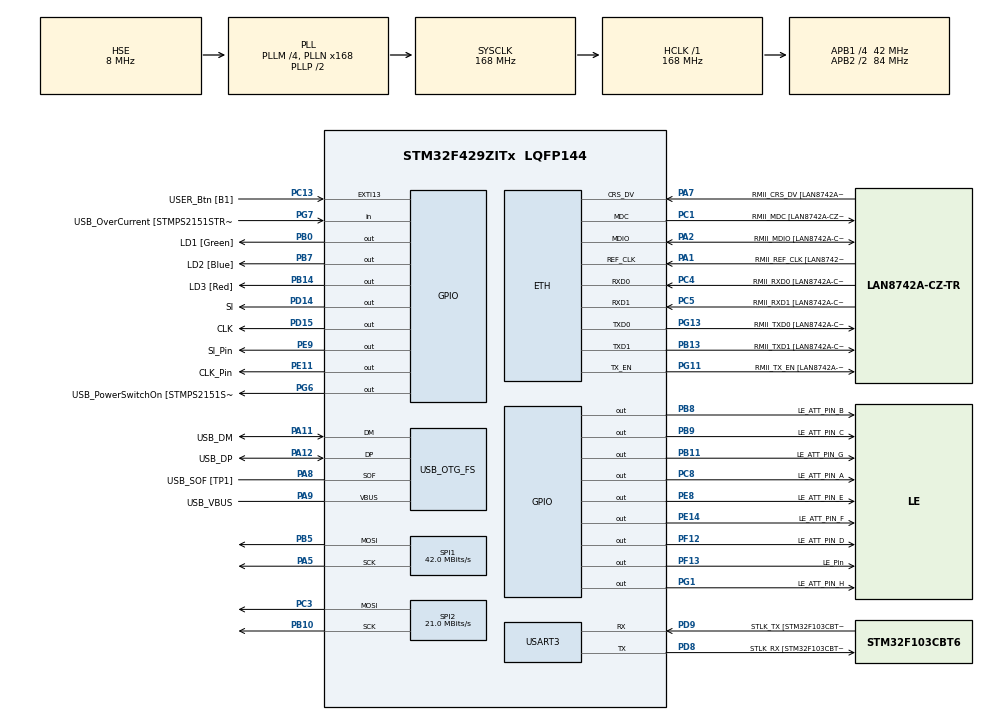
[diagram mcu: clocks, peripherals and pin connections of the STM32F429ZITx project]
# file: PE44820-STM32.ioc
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ETH.MediaInterface=HAL_ETH_RMII_MODE
ETH.PHY_Name=LAN8742A_PHY_ADDRESS
ETH.PHY_Value=0
ETH.PhyAddress=0
LWIP.BSP.number=1
LWIP.GATEWAY_ADDRESS=192.168.001.001
LWIP.IP_ADDRESS=192.168.001.110
LWIP.LWIP_DHCP=0
LWIP.LWIP_HTTPD=0
LWIP.MEM_SIZE=10*1024
LWIP.NETMASK_ADDRESS=255.255.255.000
LWIP.Version=v2.1.2_Cube
LWIP0.BSP.STBoard=false
LWIP0.BSP.api=BSP_COMPONENT_DRIVER
LWIP0.BSP.component=LAN8742
LWIP0.BSP.instance=LAN8742
LWIP0.BSP.name=Driver_PHY
LWIP0.BSP.semaphore=S_LAN8742
LWIP0.BSP.solution=LAN8742
Mcu.Family=STM32F4
Mcu.Name=STM32F429ZITx
Mcu.Package=LQFP144
NVIC.ETH_IRQn=true\:0\:0\:false\:false\:true\:true\:true\:true
NVIC.PriorityGroup=NVIC_PRIORITYGROUP_4
PA1.GPIO_Label=RMII_REF_CLK [LAN8742A-CZ-TR_REFCLK0]
PA1.Mode=RMII
PA1.Signal=ETH_REF_CLK
PA10.GPIO_Label=USB_ID
PA10.Signal=USB_OTG_FS_ID
PA11.GPIO_Label=USB_DM
PA11.Mode=Device_Only
PA11.Signal=USB_OTG_FS_DM
PA12.GPIO_Label=USB_DP
PA12.Mode=Device_Only
PA12.Signal=USB_OTG_FS_DP
PA13.GPIO_Label=TMS
PA13.Mode=Serial_Wire
PA13.Signal=SYS_JTMS-SWDIO
PA14.GPIO_Label=TCK
PA14.Mode=Serial_Wire
PA14.Signal=SYS_JTCK-SWCLK
PA2.GPIO_Label=RMII_MDIO [LAN8742A-CZ-TR_MDIO]
PA2.Mode=RMII
PA2.Signal=ETH_MDIO
PA5.Mode=TX_Only_Simplex_Unidirect_Master
PA5.Signal=SPI1_SCK
PA7.GPIO_Label=RMII_CRS_DV [LAN8742A-CZ-TR_CRS_DV]
PA7.Mode=RMII
PA7.Signal=ETH_CRS_DV
PA8.GPIO_Label=USB_SOF [TP1]
PA8.Mode=Activate_SOF_FS
PA8.Signal=USB_OTG_FS_SOF
PA9.GPIO_Label=USB_VBUS
PA9.Mode=Activate_VBUS
PA9.Signal=USB_OTG_FS_VBUS
PB0.GPIO_Label=LD1 [Green]
PB0.Signal=GPIO_Output
PB10.Mode=TX_Only_Simplex_Unidirect_Master
PB10.Signal=SPI2_SCK
PB11.GPIO_Label=LE_ATT_PIN_G
PB11.Signal=GPIO_Output
PB13.GPIO_Label=RMII_TXD1 [LAN8742A-CZ-TR_TXD1]
PB13.Mode=RMII
PB13.Signal=ETH_TXD1
PB14.GPIO_Label=LD3 [Red]
PB14.Signal=GPIO_Output
PB5.Mode=TX_Only_Simplex_Unidirect_Master
PB5.Signal=SPI1_MOSI
PB7.GPIO_Label=LD2 [Blue]
PB7.Signal=GPIO_Output
PB8.GPIO_Label=LE_ATT_PIN_B
PB8.Signal=GPIO_Output
PB9.GPIO_Label=LE_ATT_PIN_C
PB9.Signal=GPIO_Output
PC1.GPIO_Label=RMII_MDC [LAN8742A-CZ-TR_MDC]
PC1.Mode=RMII
PC1.Signal=ETH_MDC
PC13.GPIO_Label=USER_Btn [B1]
PC13.Signal=GPXTI13
PC14/OSC32_IN.Mode=LSE-External-Oscillator
PC14/OSC32_IN.Signal=RCC_OSC32_IN
PC15/OSC32_OUT.Mode=LSE-External-Oscillator
PC15/OSC32_OUT.Signal=RCC_OSC32_OUT
PC3.Mode=TX_Only_Simplex_Unidirect_Master
PC3.Signal=SPI2_MOSI
PC4.GPIO_Label=RMII_RXD0 [LAN8742A-CZ-TR_RXD0]
PC4.Mode=RMII
PC4.Signal=ETH_RXD0
PC5.GPIO_Label=RMII_RXD1 [LAN8742A-CZ-TR_RXD1]
PC5.Mode=RMII
PC5.Signal=ETH_RXD1
PC8.GPIO_Label=LE_ATT_PIN_A
PC8.Signal=GPIO_Output
PD14.GPIO_Label=SI
PD14.Signal=GPIO_Output
PD15.GPIO_Label=CLK
PD15.Signal=GPIO_Output
PD8.GPIO_Label=STLK_RX [STM32F103CBT6_PA3]
PD8.Mode=Asynchronous
PD8.Signal=USART3_TX
PD9.GPIO_Label=STLK_TX [STM32F103CBT6_PA2]
PD9.Mode=Asynchronous
PD9.Signal=USART3_RX
PE11.GPIO_Label=CLK_Pin
PE11.Signal=GPIO_Output
PE14.GPIO_Label=LE_ATT_PIN_F
PE14.Signal=GPIO_Output
PE8.GPIO_Label=LE_ATT_PIN_E
PE8.Signal=GPIO_Output
PE9.GPIO_Label=SI_Pin
PE9.Signal=GPIO_Output
PF12.GPIO_Label=LE_ATT_PIN_D
PF12.Signal=GPIO_Output
PF13.GPIO_Label=LE_Pin
PF13.Signal=GPIO_Output
PG1.GPIO_Label=LE_ATT_PIN_H
PG1.Signal=GPIO_Output
PG11.GPIO_Label=RMII_TX_EN [LAN8742A-CZ-TR_TXEN]
PG11.Mode=RMII
PG11.Signal=ETH_TX_EN
PG13.GPIO_Label=RMII_TXD0 [LAN8742A-CZ-TR_TXD0]
PG13.Mode=RMII
PG13.Signal=ETH_TXD0
PG6.GPIO_Label=USB_PowerSwitchOn [STMPS2151STR_EN]
PG6.Signal=GPIO_Output
PG7.GPIO_Label=USB_OverCurrent [STMPS2151STR_FAULT]
PG7.Signal=GPIO_Input
PH0/OSC_IN.GPIO_Label=MCO [STM32F103CBT6_PA8]
PH0/OSC_IN.Mode=HSE-External-Clock-Source
PH0/OSC_IN.Signal=RCC_OSC_IN
PH1/OSC_OUT.Mode=HSE-External-Clock-Source
PH1/OSC_OUT.Signal=RCC_OSC_OUT
ProjectManager.HeapSize=0x200
ProjectManager.StackSize=0x400
ProjectManager.TargetToolchain=STM32CubeIDE
RCC.48MHZClocksFreq_Value=48000000
RCC.AHBFreq_Value=168000000
RCC.APB1CLKDivider=RCC_HCLK_DIV4
RCC.APB1Freq_Value=42000000
RCC.APB1TimFreq_Value=84000000
RCC.APB2CLKDivider=RCC_HCLK_DIV2
RCC.APB2Freq_Value=84000000
RCC.APB2TimCLKDivider=2
RCC.APB2TimFreq_Value=168000000
RCC.CortexFreq_Value=168000000
RCC.HCLKFreq_Value=168000000
RCC.HSE_VALUE=8000000
RCC.HSI_VALUE=16000000
RCC.PLLM=4
RCC.PLLMUL=RCC_PLL_MUL9
RCC.PLLN=168
RCC.PLLQ=7
RCC.PRESCALERUSB=RCC_USBCLKSOURCE_PLL_DIV1_5
RCC.SYSCLKFreq_VALUE=168000000
RCC.SYSCLKSource=RCC_SYSCLKSOURCE_PLLCLK
RCC.SYSCLKSourceVirtual=RCC_SYSCLKSOURCE_PLLCLK
RCC.USBFreq_Value=48000000
RCC.VCOOutputFreq_Value=336000000
SPI1.CalculateBaudRate=42.0 MBits/s
SPI1.Direction=SPI_DIRECTION_2LINES
SPI1.Mode=SPI_MODE_MASTER
SPI1.VirtualType=VM_MASTER
SPI2.CalculateBaudRate=21.0 MBits/s
SPI2.Direction=SPI_DIRECTION_2LINES
SPI2.Mode=SPI_MODE_MASTER
SPI2.VirtualType=VM_MASTER
USART3.VirtualMode=VM_ASYNC
USB_OTG_FS.VirtualMode=Device_Only
VP_LWIP_VS_Enabled.Mode=Enabled
board=NUCLEO-F429ZI

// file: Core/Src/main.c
/* USER CODE BEGIN Header */
/**
  ******************************************************************************
  * @file           : main.c
  * @brief          : Main program body
  ******************************************************************************
  * @attention
  *
  * Copyright (c) 2024 STMicroelectronics.
  * All rights reserved.
  *
  * This software is licensed under terms that can be found in the LICENSE file
  * in the root directory of this software component.
  * If no LICENSE file comes with this software, it is provided AS-IS.
  *
  ******************************************************************************
  */
/* USER CODE END Header */
#include "main.h"
#include "lwip.h"

SPI_HandleTypeDef hspi1;
SPI_HandleTypeDef hspi2;

UART_HandleTypeDef huart3;

PCD_HandleTypeDef hpcd_USB_OTG_FS;

void SystemClock_Config(void);
static void MX_GPIO_Init(void);
static void MX_USART3_UART_Init(void);
static void MX_USB_OTG_FS_PCD_Init(void);
static void MX_SPI1_Init(void);
static void MX_SPI2_Init(void);

int main(void)
{

  /* MCU Configuration--------------------------------------------------------*/

  /* Reset of all peripherals, Initializes the Flash interface and the Systick. */
  HAL_Init();

  /* Configure the system clock */
  SystemClock_Config();

  /* Initialize all configured peripherals */
  MX_GPIO_Init();
  MX_USART3_UART_Init();
  MX_USB_OTG_FS_PCD_Init();
  MX_SPI1_Init();
  MX_SPI2_Init();
  MX_LWIP_Init();

  /* Infinite loop */
  while (1)
  {

  }
}

void SystemClock_Config(void)
{
  RCC_OscInitTypeDef RCC_OscInitStruct = {0};
  RCC_ClkInitTypeDef RCC_ClkInitStruct = {0};

  /** Configure the main internal regulator output voltage
  */
  __HAL_RCC_PWR_CLK_ENABLE();
  __HAL_PWR_VOLTAGESCALING_CONFIG(PWR_REGULATOR_VOLTAGE_SCALE1);

  /** Initializes the RCC Oscillators according to the specified parameters
  * in the RCC_OscInitTypeDef structure.
  */
  RCC_OscInitStruct.OscillatorType = RCC_OSCILLATORTYPE_HSE;
  RCC_OscInitStruct.HSEState = RCC_HSE_BYPASS;
  RCC_OscInitStruct.PLL.PLLState = RCC_PLL_ON;
  RCC_OscInitStruct.PLL.PLLSource = RCC_PLLSOURCE_HSE;
  RCC_OscInitStruct.PLL.PLLM = 4;
  RCC_OscInitStruct.PLL.PLLN = 168;
  RCC_OscInitStruct.PLL.PLLP = RCC_PLLP_DIV2;
  RCC_OscInitStruct.PLL.PLLQ = 7;
  if (HAL_RCC_OscConfig(&RCC_OscInitStruct) != HAL_OK)
  {
    Error_Handler();
  }

  /** Initializes the CPU, AHB and APB buses clocks
  */
  RCC_ClkInitStruct.ClockType = RCC_CLOCKTYPE_HCLK|RCC_CLOCKTYPE_SYSCLK
                              |RCC_CLOCKTYPE_PCLK1|RCC_CLOCKTYPE_PCLK2;
  RCC_ClkInitStruct.SYSCLKSource = RCC_SYSCLKSOURCE_PLLCLK;
  RCC_ClkInitStruct.AHBCLKDivider = RCC_SYSCLK_DIV1;
  RCC_ClkInitStruct.APB1CLKDivider = RCC_HCLK_DIV4;
  RCC_ClkInitStruct.APB2CLKDivider = RCC_HCLK_DIV2;

  if (HAL_RCC_ClockConfig(&RCC_ClkInitStruct, FLASH_LATENCY_5) != HAL_OK)
  {
    Error_Handler();
  }
}

static void MX_SPI1_Init(void)
{

  /* SPI1 parameter configuration*/
  hspi1.Instance = SPI1;
  hspi1.Init.Mode = SPI_MODE_MASTER;
  hspi1.Init.Direction = SPI_DIRECTION_2LINES;
  hspi1.Init.DataSize = SPI_DATASIZE_8BIT;
  hspi1.Init.CLKPolarity = SPI_POLARITY_LOW;
  hspi1.Init.CLKPhase = SPI_PHASE_1EDGE;
  hspi1.Init.NSS = SPI_NSS_SOFT;
  hspi1.Init.BaudRatePrescaler = SPI_BAUDRATEPRESCALER_2;
  hspi1.Init.FirstBit = SPI_FIRSTBIT_MSB;
  hspi1.Init.TIMode = SPI_TIMODE_DISABLE;
  hspi1.Init.CRCCalculation = SPI_CRCCALCULATION_DISABLE;
  hspi1.Init.CRCPolynomial = 10;
  if (HAL_SPI_Init(&hspi1) != HAL_OK)
  {
    Error_Handler();
  }

}

static void MX_SPI2_Init(void)
{

  /* SPI2 parameter configuration*/
  hspi2.Instance = SPI2;
  hspi2.Init.Mode = SPI_MODE_MASTER;
  hspi2.Init.Direction = SPI_DIRECTION_2LINES;
  hspi2.Init.DataSize = SPI_DATASIZE_8BIT;
  hspi2.Init.CLKPolarity = SPI_POLARITY_LOW;
  hspi2.Init.CLKPhase = SPI_PHASE_1EDGE;
  hspi2.Init.NSS = SPI_NSS_SOFT;
  hspi2.Init.BaudRatePrescaler = SPI_BAUDRATEPRESCALER_2;
  hspi2.Init.FirstBit = SPI_FIRSTBIT_MSB;
  hspi2.Init.TIMode = SPI_TIMODE_DISABLE;
  hspi2.Init.CRCCalculation = SPI_CRCCALCULATION_DISABLE;
  hspi2.Init.CRCPolynomial = 10;
  if (HAL_SPI_Init(&hspi2) != HAL_OK)
  {
    Error_Handler();
  }

}

static void MX_USART3_UART_Init(void)
{

  huart3.Instance = USART3;
  huart3.Init.BaudRate = 115200;
  huart3.Init.WordLength = UART_WORDLENGTH_8B;
  huart3.Init.StopBits = UART_STOPBITS_1;
  huart3.Init.Parity = UART_PARITY_NONE;
  huart3.Init.Mode = UART_MODE_TX_RX;
  huart3.Init.HwFlowCtl = UART_HWCONTROL_NONE;
  huart3.Init.OverSampling = UART_OVERSAMPLING_16;
  if (HAL_UART_Init(&huart3) != HAL_OK)
  {
    Error_Handler();
  }

}

static void MX_USB_OTG_FS_PCD_Init(void)
{

  hpcd_USB_OTG_FS.Instance = USB_OTG_FS;
  hpcd_USB_OTG_FS.Init.dev_endpoints = 4;
  hpcd_USB_OTG_FS.Init.speed = PCD_SPEED_FULL;
  hpcd_USB_OTG_FS.Init.dma_enable = DISABLE;
  hpcd_USB_OTG_FS.Init.phy_itface = PCD_PHY_EMBEDDED;
  hpcd_USB_OTG_FS.Init.Sof_enable = ENABLE;
  hpcd_USB_OTG_FS.Init.low_power_enable = DISABLE;
  hpcd_USB_OTG_FS.Init.lpm_enable = DISABLE;
  hpcd_USB_OTG_FS.Init.vbus_sensing_enable = ENABLE;
  hpcd_USB_OTG_FS.Init.use_dedicated_ep1 = DISABLE;
  if (HAL_PCD_Init(&hpcd_USB_OTG_FS) != HAL_OK)
  {
    Error_Handler();
  }

}

static void MX_GPIO_Init(void)
{
  GPIO_InitTypeDef GPIO_InitStruct = {0};

  /* GPIO Ports Clock Enable */
  __HAL_RCC_GPIOC_CLK_ENABLE();
  __HAL_RCC_GPIOH_CLK_ENABLE();
  __HAL_RCC_GPIOA_CLK_ENABLE();
  __HAL_RCC_GPIOB_CLK_ENABLE();
  __HAL_RCC_GPIOF_CLK_ENABLE();
  __HAL_RCC_GPIOE_CLK_ENABLE();
  __HAL_RCC_GPIOD_CLK_ENABLE();
  __HAL_RCC_GPIOG_CLK_ENABLE();

  /*Configure GPIO pin Output Level */
  HAL_GPIO_WritePin(GPIOB, LD1_Pin|LD3_Pin|LD2_Pin, GPIO_PIN_RESET);

  /*Configure GPIO pin Output Level */
  HAL_GPIO_WritePin(LE_GPIO_Port, LE_Pin, GPIO_PIN_RESET);

  /*Configure GPIO pin Output Level */
  HAL_GPIO_WritePin(GPIOE, SDI_Att_Pin|CLK_Att_Pin, GPIO_PIN_RESET);

  /*Configure GPIO pin Output Level */
  HAL_GPIO_WritePin(GPIOD, SI_Pin|CLK_Pin, GPIO_PIN_RESET);

  /*Configure GPIO pin Output Level */
  HAL_GPIO_WritePin(USB_PowerSwitchOn_GPIO_Port, USB_PowerSwitchOn_Pin, GPIO_PIN_RESET);

  /*Configure GPIO pin Output Level */
  HAL_GPIO_WritePin(LE_Att_GPIO_Port, LE_Att_Pin, GPIO_PIN_RESET);

  /*Configure GPIO pin : USER_Btn_Pin */
  GPIO_InitStruct.Pin = USER_Btn_Pin;
  GPIO_InitStruct.Mode = GPIO_MODE_IT_RISING;
  GPIO_InitStruct.Pull = GPIO_NOPULL;
  HAL_GPIO_Init(USER_Btn_GPIO_Port, &GPIO_InitStruct);

  /*Configure GPIO pins : LD1_Pin LD3_Pin LD2_Pin */
  GPIO_InitStruct.Pin = LD1_Pin|LD3_Pin|LD2_Pin;
  GPIO_InitStruct.Mode = GPIO_MODE_OUTPUT_PP;
  GPIO_InitStruct.Pull = GPIO_NOPULL;
  GPIO_InitStruct.Speed = GPIO_SPEED_FREQ_LOW;
  HAL_GPIO_Init(GPIOB, &GPIO_InitStruct);

  /*Configure GPIO pin : LE_Pin */
  GPIO_InitStruct.Pin = LE_Pin;
  GPIO_InitStruct.Mode = GPIO_MODE_OUTPUT_PP;
  GPIO_InitStruct.Pull = GPIO_NOPULL;
  GPIO_InitStruct.Speed = GPIO_SPEED_FREQ_LOW;
  HAL_GPIO_Init(LE_GPIO_Port, &GPIO_InitStruct);

  /*Configure GPIO pins : SDI_Att_Pin CLK_Att_Pin */
  GPIO_InitStruct.Pin = SDI_Att_Pin|CLK_Att_Pin;
  GPIO_InitStruct.Mode = GPIO_MODE_OUTPUT_PP;
  GPIO_InitStruct.Pull = GPIO_NOPULL;
  GPIO_InitStruct.Speed = GPIO_SPEED_FREQ_LOW;
  HAL_GPIO_Init(GPIOE, &GPIO_InitStruct);

  /*Configure GPIO pins : SI_Pin CLK_Pin */
  GPIO_InitStruct.Pin = SI_Pin|CLK_Pin;
  GPIO_InitStruct.Mode = GPIO_MODE_OUTPUT_PP;
  GPIO_InitStruct.Pull = GPIO_NOPULL;
  GPIO_InitStruct.Speed = GPIO_SPEED_FREQ_LOW;
  HAL_GPIO_Init(GPIOD, &GPIO_InitStruct);

  /*Configure GPIO pin : USB_PowerSwitchOn_Pin */
  GPIO_InitStruct.Pin = USB_PowerSwitchOn_Pin;
  GPIO_InitStruct.Mode = GPIO_MODE_OUTPUT_PP;
  GPIO_InitStruct.Pull = GPIO_NOPULL;
  GPIO_InitStruct.Speed = GPIO_SPEED_FREQ_LOW;
  HAL_GPIO_Init(USB_PowerSwitchOn_GPIO_Port, &GPIO_InitStruct);

  /*Configure GPIO pin : USB_OverCurrent_Pin */
  GPIO_InitStruct.Pin = USB_OverCurrent_Pin;
  GPIO_InitStruct.Mode = GPIO_MODE_INPUT;
  GPIO_InitStruct.Pull = GPIO_NOPULL;
  HAL_GPIO_Init(USB_OverCurrent_GPIO_Port, &GPIO_InitStruct);

  /*Configure GPIO pin : LE_Att_Pin */
  GPIO_InitStruct.Pin = LE_Att_Pin;
  GPIO_InitStruct.Mode = GPIO_MODE_OUTPUT_PP;
  GPIO_InitStruct.Pull = GPIO_NOPULL;
  GPIO_InitStruct.Speed = GPIO_SPEED_FREQ_LOW;
  HAL_GPIO_Init(LE_Att_GPIO_Port, &GPIO_InitStruct);

}

void Error_Handler(void)
{
  __disable_irq();
  while (1)
  {
  }
}
